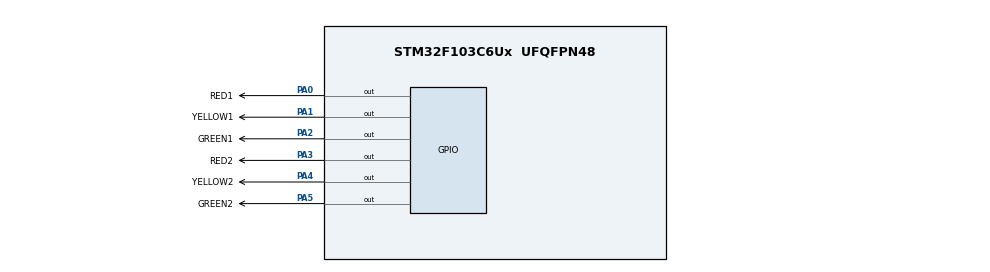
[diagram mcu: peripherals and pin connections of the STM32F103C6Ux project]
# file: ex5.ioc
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Mcu.Family=STM32F1
Mcu.Name=STM32F103C6Ux
Mcu.Package=UFQFPN48
NVIC.PriorityGroup=NVIC_PRIORITYGROUP_4
PA0-WKUP.GPIO_Label=RED1
PA0-WKUP.Signal=GPIO_Output
PA1.GPIO_Label=YELLOW1
PA1.Signal=GPIO_Output
PA2.GPIO_Label=GREEN1
PA2.Signal=GPIO_Output
PA3.GPIO_Label=RED2
PA3.Signal=GPIO_Output
PA4.GPIO_Label=YELLOW2
PA4.Signal=GPIO_Output
PA5.GPIO_Label=GREEN2
PA5.Signal=GPIO_Output
ProjectManager.HeapSize=0x200
ProjectManager.StackSize=0x400
ProjectManager.TargetToolchain=STM32CubeIDE
RCC.APB1Freq_Value=8000000
RCC.APB2Freq_Value=8000000
VP_SYS_VS_ND.Mode=No_Debug
board=custom

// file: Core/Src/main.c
/* USER CODE BEGIN Header */
/**
  ******************************************************************************
  * @file           : main.c
  * @brief          : Main program body - Ex5 (Traffic Light + 7-Segment Countdown)
  ******************************************************************************
  * @attention
  *
  * Copyright (c) 2026 STMicroelectronics.
  * All rights reserved.
  *
  * This software is licensed under terms that can be found in the LICENSE file
  * in the root directory of this software component.
  * If no LICENSE file comes with this software, it is provided AS-IS.
  *
  ******************************************************************************
  */
/* USER CODE END Header */
#include "main.h"

void SystemClock_Config(void);
static void MX_GPIO_Init(void);
/* USER CODE BEGIN PFP */
void display7SEG(int num);
void countdownDelay(int seconds);
/* USER CODE END PFP */

/* USER CODE BEGIN 0 */

/* ---- 4-way traffic light -------------------------------------------------
 * North + South share PA0(Red), PA1(Yellow), PA2(Green)
 * East  + West  share PA3(Red), PA4(Yellow), PA5(Green)
 * LEDs are wired active-LOW (cathode to MCU pin), so we invert the
 * logical value before writing: passing GPIO_PIN_SET means "turn this
 * light ON" from the caller's point of view.
 * ------------------------------------------------------------------------ */
void setNS(GPIO_PinState r, GPIO_PinState y, GPIO_PinState g) {
    HAL_GPIO_WritePin(GPIOA, GPIO_PIN_0, (GPIO_PinState)!r);
    HAL_GPIO_WritePin(GPIOA, GPIO_PIN_1, (GPIO_PinState)!y);
    HAL_GPIO_WritePin(GPIOA, GPIO_PIN_2, (GPIO_PinState)!g);
}

void setEW(GPIO_PinState r, GPIO_PinState y, GPIO_PinState g) {
    HAL_GPIO_WritePin(GPIOA, GPIO_PIN_3, (GPIO_PinState)!r);
    HAL_GPIO_WritePin(GPIOA, GPIO_PIN_4, (GPIO_PinState)!y);
    HAL_GPIO_WritePin(GPIOA, GPIO_PIN_5, (GPIO_PinState)!g);
}

void countdownDelay(int seconds) {
    for (int i = seconds; i > 0; i--) {
        display7SEG(i);
        HAL_Delay(1000);
    }
}

/* ---- 7-segment display (common anode, active-LOW segments) --------------
 * Segment order: a=PB0 b=PB1 c=PB2 d=PB3 e=PB4 f=PB5 g=PB6
 * segOn[n][i] = 1 means "segment i should be lit" for digit n.
 * ------------------------------------------------------------------------ */
void display7SEG(int num) {
    const uint8_t segOn[10][7] = {
        {1,1,1,1,1,1,0}, // 0
        {0,1,1,0,0,0,0}, // 1
        {1,1,0,1,1,0,1}, // 2
        {1,1,1,1,0,0,1}, // 3
        {0,1,1,0,0,1,1}, // 4
        {1,0,1,1,0,1,1}, // 5
        {1,0,1,1,1,1,1}, // 6
        {1,1,1,0,0,0,0}, // 7
        {1,1,1,1,1,1,1}, // 8
        {1,1,1,1,0,1,1}  // 9
    };
    if (num < 0 || num > 9) return;
    for (int i = 0; i < 7; i++) {
        HAL_GPIO_WritePin(GPIOB, (uint16_t)(1 << i),
            segOn[num][i] ? GPIO_PIN_RESET : GPIO_PIN_SET); // active-low
    }
}

/* USER CODE END 0 */

int main(void)
{

  /* MCU Configuration--------------------------------------------------------*/

  /* Reset of all peripherals, Initializes the Flash interface and the Systick. */
  HAL_Init();

  /* Configure the system clock */
  SystemClock_Config();

  /* Initialize all configured peripherals */
  MX_GPIO_Init();

  /* Infinite loop */
  /* USER CODE BEGIN WHILE */
  while (1)
  {
      setNS(GPIO_PIN_SET, GPIO_PIN_RESET, GPIO_PIN_RESET);   // NS red
      setEW(GPIO_PIN_RESET, GPIO_PIN_RESET, GPIO_PIN_SET);   // EW green
      countdownDelay(3); // GREEN duration, đếm ngược 3-2-1

      setEW(GPIO_PIN_RESET, GPIO_PIN_SET, GPIO_PIN_RESET);   // EW yellow
      countdownDelay(2); // YELLOW

      setNS(GPIO_PIN_RESET, GPIO_PIN_RESET, GPIO_PIN_SET);   // NS green
      setEW(GPIO_PIN_SET, GPIO_PIN_RESET, GPIO_PIN_RESET);   // EW red
      countdownDelay(3); // GREEN

      setNS(GPIO_PIN_RESET, GPIO_PIN_SET, GPIO_PIN_RESET);   // NS yellow
      countdownDelay(2); // YELLOW đếm ngược 2-1
    /* USER CODE END WHILE */

  }
}

void SystemClock_Config(void)
{
  RCC_OscInitTypeDef RCC_OscInitStruct = {0};
  RCC_ClkInitTypeDef RCC_ClkInitStruct = {0};

  /** Initializes the RCC Oscillators according to the specified parameters
  * in the RCC_OscInitTypeDef structure.
  */
  RCC_OscInitStruct.OscillatorType = RCC_OSCILLATORTYPE_HSI;
  RCC_OscInitStruct.HSIState = RCC_HSI_ON;
  RCC_OscInitStruct.HSICalibrationValue = RCC_HSICALIBRATION_DEFAULT;
  RCC_OscInitStruct.PLL.PLLState = RCC_PLL_NONE;
  if (HAL_RCC_OscConfig(&RCC_OscInitStruct) != HAL_OK)
  {
    Error_Handler();
  }

  /** Initializes the CPU, AHB and APB buses clocks
  */
  RCC_ClkInitStruct.ClockType = RCC_CLOCKTYPE_HCLK|RCC_CLOCKTYPE_SYSCLK
                              |RCC_CLOCKTYPE_PCLK1|RCC_CLOCKTYPE_PCLK2;
  RCC_ClkInitStruct.SYSCLKSource = RCC_SYSCLKSOURCE_HSI;
  RCC_ClkInitStruct.AHBCLKDivider = RCC_SYSCLK_DIV1;
  RCC_ClkInitStruct.APB1CLKDivider = RCC_HCLK_DIV1;
  RCC_ClkInitStruct.APB2CLKDivider = RCC_HCLK_DIV1;

  if (HAL_RCC_ClockConfig(&RCC_ClkInitStruct, FLASH_LATENCY_0) != HAL_OK)
  {
    Error_Handler();
  }
}

static void MX_GPIO_Init(void)
{
  GPIO_InitTypeDef GPIO_InitStruct = {0};

  /* GPIO Ports Clock Enable */
  __HAL_RCC_GPIOA_CLK_ENABLE();
  __HAL_RCC_GPIOB_CLK_ENABLE();

  /* Set all traffic-light pins HIGH at start (LEDs OFF, since active-low) */
  HAL_GPIO_WritePin(GPIOA, GPIO_PIN_0|GPIO_PIN_1|GPIO_PIN_2|GPIO_PIN_3
                          |GPIO_PIN_4|GPIO_PIN_5, GPIO_PIN_SET);

  /* Set all 7-segment pins HIGH at start (segments OFF, since active-low) */
  HAL_GPIO_WritePin(GPIOB, GPIO_PIN_0|GPIO_PIN_1|GPIO_PIN_2|GPIO_PIN_3
                          |GPIO_PIN_4|GPIO_PIN_5|GPIO_PIN_6, GPIO_PIN_SET);

  /* Configure GPIO pins : PA0 PA1 PA2 PA3 PA4 PA5 (traffic light) */
  GPIO_InitStruct.Pin = GPIO_PIN_0|GPIO_PIN_1|GPIO_PIN_2|GPIO_PIN_3
                          |GPIO_PIN_4|GPIO_PIN_5;
  GPIO_InitStruct.Mode = GPIO_MODE_OUTPUT_PP;
  GPIO_InitStruct.Pull = GPIO_NOPULL;
  GPIO_InitStruct.Speed = GPIO_SPEED_FREQ_LOW;
  HAL_GPIO_Init(GPIOA, &GPIO_InitStruct);

  /* Configure GPIO pins : PB0 PB1 PB2 PB3 PB4 PB5 PB6 (7-segment) */
  GPIO_InitStruct.Pin = GPIO_PIN_0|GPIO_PIN_1|GPIO_PIN_2|GPIO_PIN_3
                          |GPIO_PIN_4|GPIO_PIN_5|GPIO_PIN_6;
  GPIO_InitStruct.Mode = GPIO_MODE_OUTPUT_PP;
  GPIO_InitStruct.Pull = GPIO_NOPULL;
  GPIO_InitStruct.Speed = GPIO_SPEED_FREQ_LOW;
  HAL_GPIO_Init(GPIOB, &GPIO_InitStruct);

}

void Error_Handler(void)
{
  __disable_irq();
  while (1)
  {
  }
}
